VERSION 5.7 ;
  NOWIREEXTENSIONATPIN ON ;
  DIVIDERCHAR "/" ;
  BUSBITCHARS "[]" ;
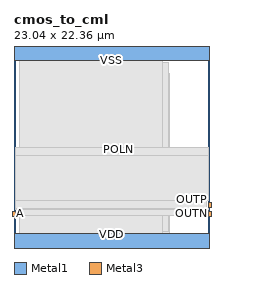
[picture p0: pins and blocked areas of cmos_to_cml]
MACRO cmos_to_cml
  CLASS BLOCK ;
  FOREIGN cmos_to_cml ;
  ORIGIN 0.000 0.000 ;
  SIZE 23.040 BY 22.360 ;
  PIN VDD
    DIRECTION INOUT ;
    USE POWER ;
    PORT
      LAYER Metal1 ;
        RECT 0.000 -1.000 23.040 1.000 ;
    END
  END VDD
  PIN VSS
    DIRECTION INOUT ;
    USE GROUND ;
    PORT
      LAYER Metal1 ;
        RECT 0.000 21.360 23.040 23.360 ;
    END
  END VSS
  PIN A
    DIRECTION INPUT ;
    USE SIGNAL ;
    ANTENNAGATEAREA 1.612000 ;
    PORT
      LAYER Metal3 ;
        RECT -0.150 3.000 0.150 3.600 ;
    END
  END A
  PIN OUTN
    DIRECTION OUTPUT ;
    USE SIGNAL ;
    ANTENNADIFFAREA 1.696000 ;
    PORT
      LAYER Metal3 ;
        RECT 22.890 3.000 23.190 3.600 ;
    END
  END OUTN
  PIN OUTP
    DIRECTION OUTPUT ;
    USE SIGNAL ;
    ANTENNADIFFAREA 1.696000 ;
    PORT
      LAYER Metal3 ;
        RECT 22.890 4.100 23.190 4.700 ;
    END
  END OUTP
  PIN POLN
    DIRECTION INPUT ;
    USE SIGNAL ;
    ANTENNAGATEAREA 1.114100 ;
    PORT
      LAYER Metal3 ;
        RECT 12.130 10.400 12.430 11.480 ;
    END
  END POLN
  OBS
      LAYER GatPoly ;
        RECT 0.600 0.150 18.250 19.810 ;
      LAYER Metal1 ;
        RECT 0.640 1.180 18.180 21.180 ;
      LAYER Metal2 ;
        RECT 0.600 0.000 17.470 21.660 ;
        RECT 7.600 -0.050 7.820 0.000 ;
        RECT 17.120 -0.050 17.340 0.000 ;
      LAYER Metal3 ;
        RECT 0.150 10.190 11.920 11.180 ;
        RECT 12.640 10.190 22.890 11.180 ;
        RECT 0.150 4.910 22.890 10.190 ;
        RECT 0.150 3.890 22.680 4.910 ;
        RECT 0.150 3.810 22.890 3.890 ;
        RECT 0.360 3.150 22.680 3.810 ;
  END
END cmos_to_cml
END LIBRARY

